VERSION 5.7 ;
BUSBITCHARS "[]" ;
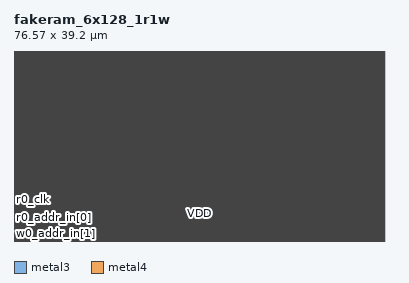
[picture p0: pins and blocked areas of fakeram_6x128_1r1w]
MACRO fakeram_6x128_1r1w
  FOREIGN fakeram_6x128_1r1w 0 0 ;
  SYMMETRY X Y R90 ;
  SIZE 76.570 BY 39.200 ;
  CLASS BLOCK ;
  PIN w0_wd_in[0]
    DIRECTION INPUT ;
    USE SIGNAL ;
    SHAPE ABUTMENT ;
    PORT
      LAYER metal3 ;
      RECT 0.000 0.280 0.140 0.420 ;
    END
  END w0_wd_in[0]
  PIN w0_wd_in[1]
    DIRECTION INPUT ;
    USE SIGNAL ;
    SHAPE ABUTMENT ;
    PORT
      LAYER metal3 ;
      RECT 0.000 0.560 0.140 0.700 ;
    END
  END w0_wd_in[1]
  PIN w0_wd_in[2]
    DIRECTION INPUT ;
    USE SIGNAL ;
    SHAPE ABUTMENT ;
    PORT
      LAYER metal3 ;
      RECT 0.000 0.840 0.140 0.980 ;
    END
  END w0_wd_in[2]
  PIN w0_wd_in[3]
    DIRECTION INPUT ;
    USE SIGNAL ;
    SHAPE ABUTMENT ;
    PORT
      LAYER metal3 ;
      RECT 0.000 1.120 0.140 1.260 ;
    END
  END w0_wd_in[3]
  PIN w0_wd_in[4]
    DIRECTION INPUT ;
    USE SIGNAL ;
    SHAPE ABUTMENT ;
    PORT
      LAYER metal3 ;
      RECT 0.000 1.400 0.140 1.540 ;
    END
  END w0_wd_in[4]
  PIN w0_wd_in[5]
    DIRECTION INPUT ;
    USE SIGNAL ;
    SHAPE ABUTMENT ;
    PORT
      LAYER metal3 ;
      RECT 0.000 1.680 0.140 1.820 ;
    END
  END w0_wd_in[5]
  PIN w0_addr_in[0]
    DIRECTION INPUT ;
    USE SIGNAL ;
    SHAPE ABUTMENT ;
    PORT
      LAYER metal3 ;
      RECT 0.000 1.960 0.140 2.100 ;
    END
  END w0_addr_in[0]
  PIN w0_addr_in[1]
    DIRECTION INPUT ;
    USE SIGNAL ;
    SHAPE ABUTMENT ;
    PORT
      LAYER metal3 ;
      RECT 0.000 2.240 0.140 2.380 ;
    END
  END w0_addr_in[1]
  PIN w0_addr_in[2]
    DIRECTION INPUT ;
    USE SIGNAL ;
    SHAPE ABUTMENT ;
    PORT
      LAYER metal3 ;
      RECT 0.000 2.520 0.140 2.660 ;
    END
  END w0_addr_in[2]
  PIN w0_addr_in[3]
    DIRECTION INPUT ;
    USE SIGNAL ;
    SHAPE ABUTMENT ;
    PORT
      LAYER metal3 ;
      RECT 0.000 2.800 0.140 2.940 ;
    END
  END w0_addr_in[3]
  PIN w0_addr_in[4]
    DIRECTION INPUT ;
    USE SIGNAL ;
    SHAPE ABUTMENT ;
    PORT
      LAYER metal3 ;
      RECT 0.000 3.080 0.140 3.220 ;
    END
  END w0_addr_in[4]
  PIN w0_addr_in[5]
    DIRECTION INPUT ;
    USE SIGNAL ;
    SHAPE ABUTMENT ;
    PORT
      LAYER metal3 ;
      RECT 0.000 3.360 0.140 3.500 ;
    END
  END w0_addr_in[5]
  PIN w0_addr_in[6]
    DIRECTION INPUT ;
    USE SIGNAL ;
    SHAPE ABUTMENT ;
    PORT
      LAYER metal3 ;
      RECT 0.000 3.640 0.140 3.780 ;
    END
  END w0_addr_in[6]
  PIN w0_clk
    DIRECTION INPUT ;
    USE SIGNAL ;
    SHAPE ABUTMENT ;
    PORT
      LAYER metal3 ;
      RECT 0.000 3.920 0.140 4.060 ;
    END
  END w0_clk
  PIN w0_ce_in
    DIRECTION INPUT ;
    USE SIGNAL ;
    SHAPE ABUTMENT ;
    PORT
      LAYER metal3 ;
      RECT 0.000 4.200 0.140 4.340 ;
    END
  END w0_ce_in
  PIN w0_we_in
    DIRECTION INPUT ;
    USE SIGNAL ;
    SHAPE ABUTMENT ;
    PORT
      LAYER metal3 ;
      RECT 0.000 4.480 0.140 4.620 ;
    END
  END w0_we_in
  PIN r0_rd_out[0]
    DIRECTION OUTPUT ;
    USE SIGNAL ;
    SHAPE ABUTMENT ;
    PORT
      LAYER metal3 ;
      RECT 0.000 4.760 0.140 4.900 ;
    END
  END r0_rd_out[0]
  PIN r0_rd_out[1]
    DIRECTION OUTPUT ;
    USE SIGNAL ;
    SHAPE ABUTMENT ;
    PORT
      LAYER metal3 ;
      RECT 0.000 5.040 0.140 5.180 ;
    END
  END r0_rd_out[1]
  PIN r0_rd_out[2]
    DIRECTION OUTPUT ;
    USE SIGNAL ;
    SHAPE ABUTMENT ;
    PORT
      LAYER metal3 ;
      RECT 0.000 5.320 0.140 5.460 ;
    END
  END r0_rd_out[2]
  PIN r0_rd_out[3]
    DIRECTION OUTPUT ;
    USE SIGNAL ;
    SHAPE ABUTMENT ;
    PORT
      LAYER metal3 ;
      RECT 0.000 5.600 0.140 5.740 ;
    END
  END r0_rd_out[3]
  PIN r0_rd_out[4]
    DIRECTION OUTPUT ;
    USE SIGNAL ;
    SHAPE ABUTMENT ;
    PORT
      LAYER metal3 ;
      RECT 0.000 5.880 0.140 6.020 ;
    END
  END r0_rd_out[4]
  PIN r0_rd_out[5]
    DIRECTION OUTPUT ;
    USE SIGNAL ;
    SHAPE ABUTMENT ;
    PORT
      LAYER metal3 ;
      RECT 0.000 6.160 0.140 6.300 ;
    END
  END r0_rd_out[5]
  PIN r0_addr_in[0]
    DIRECTION INPUT ;
    USE SIGNAL ;
    SHAPE ABUTMENT ;
    PORT
      LAYER metal3 ;
      RECT 0.000 6.440 0.140 6.580 ;
    END
  END r0_addr_in[0]
  PIN r0_addr_in[1]
    DIRECTION INPUT ;
    USE SIGNAL ;
    SHAPE ABUTMENT ;
    PORT
      LAYER metal3 ;
      RECT 0.000 6.720 0.140 6.860 ;
    END
  END r0_addr_in[1]
  PIN r0_addr_in[2]
    DIRECTION INPUT ;
    USE SIGNAL ;
    SHAPE ABUTMENT ;
    PORT
      LAYER metal3 ;
      RECT 0.000 7.000 0.140 7.140 ;
    END
  END r0_addr_in[2]
  PIN r0_addr_in[3]
    DIRECTION INPUT ;
    USE SIGNAL ;
    SHAPE ABUTMENT ;
    PORT
      LAYER metal3 ;
      RECT 0.000 7.280 0.140 7.420 ;
    END
  END r0_addr_in[3]
  PIN r0_addr_in[4]
    DIRECTION INPUT ;
    USE SIGNAL ;
    SHAPE ABUTMENT ;
    PORT
      LAYER metal3 ;
      RECT 0.000 7.560 0.140 7.700 ;
    END
  END r0_addr_in[4]
  PIN r0_addr_in[5]
    DIRECTION INPUT ;
    USE SIGNAL ;
    SHAPE ABUTMENT ;
    PORT
      LAYER metal3 ;
      RECT 0.000 7.840 0.140 7.980 ;
    END
  END r0_addr_in[5]
  PIN r0_addr_in[6]
    DIRECTION INPUT ;
    USE SIGNAL ;
    SHAPE ABUTMENT ;
    PORT
      LAYER metal3 ;
      RECT 0.000 8.120 0.140 8.260 ;
    END
  END r0_addr_in[6]
  PIN r0_clk
    DIRECTION INPUT ;
    USE SIGNAL ;
    SHAPE ABUTMENT ;
    PORT
      LAYER metal3 ;
      RECT 0.000 8.400 0.140 8.540 ;
    END
  END r0_clk
  PIN r0_ce_in
    DIRECTION INPUT ;
    USE SIGNAL ;
    SHAPE ABUTMENT ;
    PORT
      LAYER metal3 ;
      RECT 0.000 8.680 0.140 8.820 ;
    END
  END r0_ce_in
  PIN VDD
    DIRECTION INOUT ;
    USE POWER ;
    PORT
      LAYER metal4 ;
      RECT 0.190 0.000 76.380 0.140 ;
      RECT 0.190 0.560 76.380 0.700 ;
      RECT 0.190 1.120 76.380 1.260 ;
      RECT 0.190 1.680 76.380 1.820 ;
      RECT 0.190 2.240 76.380 2.380 ;
      RECT 0.190 2.800 76.380 2.940 ;
      RECT 0.190 3.360 76.380 3.500 ;
      RECT 0.190 3.920 76.380 4.060 ;
      RECT 0.190 4.480 76.380 4.620 ;
      RECT 0.190 5.040 76.380 5.180 ;
      RECT 0.190 5.600 76.380 5.740 ;
      RECT 0.190 6.160 76.380 6.300 ;
      RECT 0.190 6.720 76.380 6.860 ;
      RECT 0.190 7.280 76.380 7.420 ;
      RECT 0.190 7.840 76.380 7.980 ;
      RECT 0.190 8.400 76.380 8.540 ;
      RECT 0.190 8.960 76.380 9.100 ;
      RECT 0.190 9.520 76.380 9.660 ;
      RECT 0.190 10.080 76.380 10.220 ;
      RECT 0.190 10.640 76.380 10.780 ;
      RECT 0.190 11.200 76.380 11.340 ;
      RECT 0.190 11.760 76.380 11.900 ;
      RECT 0.190 12.320 76.380 12.460 ;
      RECT 0.190 12.880 76.380 13.020 ;
      RECT 0.190 13.440 76.380 13.580 ;
      RECT 0.190 14.000 76.380 14.140 ;
      RECT 0.190 14.560 76.380 14.700 ;
      RECT 0.190 15.120 76.380 15.260 ;
      RECT 0.190 15.680 76.380 15.820 ;
      RECT 0.190 16.240 76.380 16.380 ;
      RECT 0.190 16.800 76.380 16.940 ;
      RECT 0.190 17.360 76.380 17.500 ;
      RECT 0.190 17.920 76.380 18.060 ;
      RECT 0.190 18.480 76.380 18.620 ;
      RECT 0.190 19.040 76.380 19.180 ;
      RECT 0.190 19.600 76.380 19.740 ;
      RECT 0.190 20.160 76.380 20.300 ;
      RECT 0.190 20.720 76.380 20.860 ;
      RECT 0.190 21.280 76.380 21.420 ;
      RECT 0.190 21.840 76.380 21.980 ;
      RECT 0.190 22.400 76.380 22.540 ;
      RECT 0.190 22.960 76.380 23.100 ;
      RECT 0.190 23.520 76.380 23.660 ;
      RECT 0.190 24.080 76.380 24.220 ;
      RECT 0.190 24.640 76.380 24.780 ;
      RECT 0.190 25.200 76.380 25.340 ;
      RECT 0.190 25.760 76.380 25.900 ;
      RECT 0.190 26.320 76.380 26.460 ;
      RECT 0.190 26.880 76.380 27.020 ;
      RECT 0.190 27.440 76.380 27.580 ;
      RECT 0.190 28.000 76.380 28.140 ;
      RECT 0.190 28.560 76.380 28.700 ;
      RECT 0.190 29.120 76.380 29.260 ;
      RECT 0.190 29.680 76.380 29.820 ;
      RECT 0.190 30.240 76.380 30.380 ;
      RECT 0.190 30.800 76.380 30.940 ;
      RECT 0.190 31.360 76.380 31.500 ;
      RECT 0.190 31.920 76.380 32.060 ;
      RECT 0.190 32.480 76.380 32.620 ;
      RECT 0.190 33.040 76.380 33.180 ;
      RECT 0.190 33.600 76.380 33.740 ;
      RECT 0.190 34.160 76.380 34.300 ;
      RECT 0.190 34.720 76.380 34.860 ;
      RECT 0.190 35.280 76.380 35.420 ;
      RECT 0.190 35.840 76.380 35.980 ;
      RECT 0.190 36.400 76.380 36.540 ;
      RECT 0.190 36.960 76.380 37.100 ;
      RECT 0.190 37.520 76.380 37.660 ;
      RECT 0.190 38.080 76.380 38.220 ;
      RECT 0.190 38.640 76.380 38.780 ;
    END
  END VDD
  PIN VSS
    DIRECTION INOUT ;
    USE GROUND ;
    PORT
      LAYER metal4 ;
      RECT 0.190 0.280 76.380 0.420 ;
      RECT 0.190 0.840 76.380 0.980 ;
      RECT 0.190 1.400 76.380 1.540 ;
      RECT 0.190 1.960 76.380 2.100 ;
      RECT 0.190 2.520 76.380 2.660 ;
      RECT 0.190 3.080 76.380 3.220 ;
      RECT 0.190 3.640 76.380 3.780 ;
      RECT 0.190 4.200 76.380 4.340 ;
      RECT 0.190 4.760 76.380 4.900 ;
      RECT 0.190 5.320 76.380 5.460 ;
      RECT 0.190 5.880 76.380 6.020 ;
      RECT 0.190 6.440 76.380 6.580 ;
      RECT 0.190 7.000 76.380 7.140 ;
      RECT 0.190 7.560 76.380 7.700 ;
      RECT 0.190 8.120 76.380 8.260 ;
      RECT 0.190 8.680 76.380 8.820 ;
      RECT 0.190 9.240 76.380 9.380 ;
      RECT 0.190 9.800 76.380 9.940 ;
      RECT 0.190 10.360 76.380 10.500 ;
      RECT 0.190 10.920 76.380 11.060 ;
      RECT 0.190 11.480 76.380 11.620 ;
      RECT 0.190 12.040 76.380 12.180 ;
      RECT 0.190 12.600 76.380 12.740 ;
      RECT 0.190 13.160 76.380 13.300 ;
      RECT 0.190 13.720 76.380 13.860 ;
      RECT 0.190 14.280 76.380 14.420 ;
      RECT 0.190 14.840 76.380 14.980 ;
      RECT 0.190 15.400 76.380 15.540 ;
      RECT 0.190 15.960 76.380 16.100 ;
      RECT 0.190 16.520 76.380 16.660 ;
      RECT 0.190 17.080 76.380 17.220 ;
      RECT 0.190 17.640 76.380 17.780 ;
      RECT 0.190 18.200 76.380 18.340 ;
      RECT 0.190 18.760 76.380 18.900 ;
      RECT 0.190 19.320 76.380 19.460 ;
      RECT 0.190 19.880 76.380 20.020 ;
      RECT 0.190 20.440 76.380 20.580 ;
      RECT 0.190 21.000 76.380 21.140 ;
      RECT 0.190 21.560 76.380 21.700 ;
      RECT 0.190 22.120 76.380 22.260 ;
      RECT 0.190 22.680 76.380 22.820 ;
      RECT 0.190 23.240 76.380 23.380 ;
      RECT 0.190 23.800 76.380 23.940 ;
      RECT 0.190 24.360 76.380 24.500 ;
      RECT 0.190 24.920 76.380 25.060 ;
      RECT 0.190 25.480 76.380 25.620 ;
      RECT 0.190 26.040 76.380 26.180 ;
      RECT 0.190 26.600 76.380 26.740 ;
      RECT 0.190 27.160 76.380 27.300 ;
      RECT 0.190 27.720 76.380 27.860 ;
      RECT 0.190 28.280 76.380 28.420 ;
      RECT 0.190 28.840 76.380 28.980 ;
      RECT 0.190 29.400 76.380 29.540 ;
      RECT 0.190 29.960 76.380 30.100 ;
      RECT 0.190 30.520 76.380 30.660 ;
      RECT 0.190 31.080 76.380 31.220 ;
      RECT 0.190 31.640 76.380 31.780 ;
      RECT 0.190 32.200 76.380 32.340 ;
      RECT 0.190 32.760 76.380 32.900 ;
      RECT 0.190 33.320 76.380 33.460 ;
      RECT 0.190 33.880 76.380 34.020 ;
      RECT 0.190 34.440 76.380 34.580 ;
      RECT 0.190 35.000 76.380 35.140 ;
      RECT 0.190 35.560 76.380 35.700 ;
      RECT 0.190 36.120 76.380 36.260 ;
      RECT 0.190 36.680 76.380 36.820 ;
      RECT 0.190 37.240 76.380 37.380 ;
      RECT 0.190 37.800 76.380 37.940 ;
      RECT 0.190 38.360 76.380 38.500 ;
      RECT 0.190 38.920 76.380 39.060 ;
    END
  END VSS
  OBS
    LAYER metal1 ;
      RECT 0.000 0.000 76.570 39.200 ;
    LAYER metal2 ;
      RECT 0.000 0.000 76.570 39.200 ;
    LAYER metal3 ;
      RECT 0.000 0.000 76.570 39.200 ;
  END
END fakeram_6x128_1r1w
END LIBRARY
